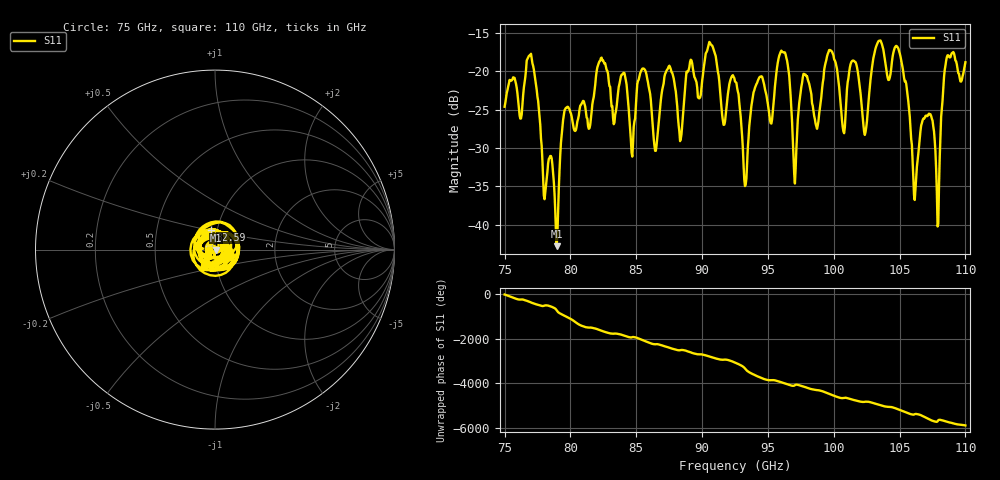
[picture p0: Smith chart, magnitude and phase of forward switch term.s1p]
!Created with skrf (http://scikit-rf.org).
# GHz S RI R 50.0
!freq ReS11 ImS11
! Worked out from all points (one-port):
!   647 points, 75 GHz to 110 GHz, reference 50 ohm
!   lowest |S11| = -42.8 dB at 78.96 GHz (marker M1), VSWR 1.01, Z = 50.7 - j0.225 ohm
!   |S11| at or under -10 dB: start of sweep to end of sweep
!   S11 on the Smith chart (normalised r, x): 75 GHz: 1.10, -0.08; 82.59 GHz: 0.93, +0.21; 110 GHz: 0.87, -0.17
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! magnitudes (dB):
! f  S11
! 75 GHz  -24.6
! 77.01 GHz  -17.7
! 78.96 GHz  -42.8
! 79.39 GHz  -27.2
! 82.59 GHz  -19.0
! 83.78 GHz  -21.2
! 84.65 GHz  -30.6
! 85.51 GHz  -19.6
! 86.43 GHz  -30.4
! 87.41 GHz  -19.6
! 88.17 GHz  -26.0
! 90.6 GHz  -16.3
! 91.63 GHz  -27.0
! 92.5 GHz  -21.3
! 93.26 GHz  -35.0
! 94.02 GHz  -22.2
! 95.26 GHz  -26.8
! 96.02 GHz  -17.3
! 96.89 GHz  -28.9
! 101.3 GHz  -19.1
! 102.4 GHz  -28.3
! 103.4 GHz  -16.0
! 105.7 GHz  -24.0
! 106.2 GHz  -36.8
! 107.2 GHz  -25.5
! 107.9 GHz  -40.2
! 108.5 GHz  -18.6
! 110 GHz  -18.8
